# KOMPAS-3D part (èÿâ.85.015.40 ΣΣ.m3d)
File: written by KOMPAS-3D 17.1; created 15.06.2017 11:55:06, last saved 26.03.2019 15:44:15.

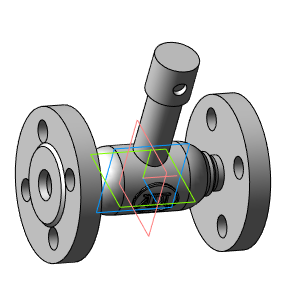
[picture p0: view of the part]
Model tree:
1. Операция без истории:2  (labels: Сталь 20  ГОСТ 1050-88)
